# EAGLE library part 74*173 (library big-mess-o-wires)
4-bit D type REGISTER, 3-state

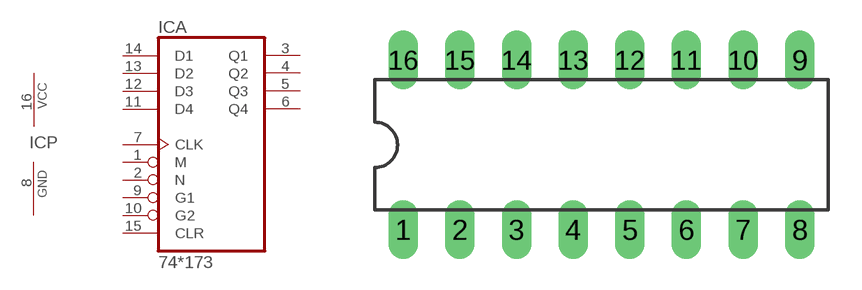
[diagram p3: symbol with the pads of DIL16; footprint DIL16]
Designator prefix IC; gates A=74173 P=PWRN

## 74LS173N  [DIL16]
1  A:M  in
2  A:N  in
3  A:Q1  hiz
4  A:Q2  hiz
5  A:Q3  hiz
6  A:Q4  hiz
7  A:CLK  in
8  P:GND  pwr
9  A:G1  in
10  A:G2  in
11  A:D4  in
12  A:D3  in
13  A:D2  in
14  A:D1  in
15  A:CLR  in
16  P:VCC  pwr

## Footprint DIL16 (pad centres in mm)
Dual In Line Package
drill 0.813 long: 1 -8.89,-3.81; 2 -6.35,-3.81; 3 -3.81,-3.81; 4 -1.27,-3.81; 5 1.27,-3.81; 6 3.81,-3.81; 7 6.35,-3.81; 8 8.89,-3.81; 9 8.89,3.81; 10 6.35,3.81; 11 3.81,3.81; 12 1.27,3.81; 13 -1.27,3.81; 14 -3.81,3.81; 15 -6.35,3.81; 16 -8.89,3.81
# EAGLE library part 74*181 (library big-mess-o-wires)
ARITHMETIC LOGIC UNIT function generator

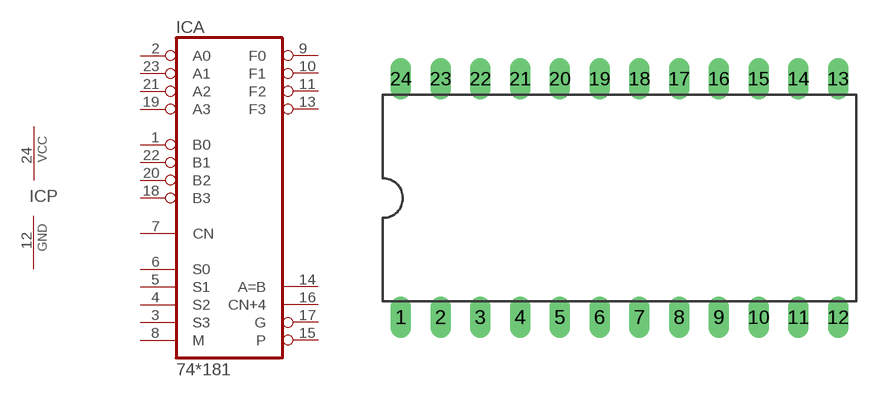
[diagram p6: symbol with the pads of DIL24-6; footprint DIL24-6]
Designator prefix IC; gates A=74181 P=PWRN

## 74LS181N, 74S181N  [DIL24-6]
1  A:B0  in
2  A:A0  in
3  A:S3  in
4  A:S2  in
5  A:S1  in
6  A:S0  in
7  A:CN  in
8  A:M  in
9  A:F0  out
10  A:F1  out
11  A:F2  out
12  P:GND  pwr
13  A:F3  out
14  A:A=B  out
15  A:P  out
16  A:CN+4  out
17  A:G  out
18  A:B3  in
19  A:A3  in
20  A:B2  in
21  A:A2  in
22  A:B1  in
23  A:A1  in
24  P:VCC  pwr

## Footprint DIL24-6 (pad centres in mm)
Dual In Line Package 0.6 inch
drill 0.813 long: 1 -13.97,-7.62; 2 -11.43,-7.62; 3 -8.89,-7.62; 4 -6.35,-7.62; 5 -3.81,-7.62; 6 -1.27,-7.62; 7 1.27,-7.62; 8 3.81,-7.62; 9 6.35,-7.62; 10 8.89,-7.62; 11 11.43,-7.62; 12 13.97,-7.62; 13 13.97,7.62; 14 11.43,7.62; 15 8.89,7.62; 16 6.35,7.62; 17 3.81,7.62; 18 1.27,7.62; 19 -1.27,7.62; 20 -3.81,7.62; 21 -6.35,7.62; 22 -8.89,7.62; 23 -11.43,7.62; 24 -13.97,7.62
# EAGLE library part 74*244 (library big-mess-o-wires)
Octal BUFFER and LINE DRIVER, 3-state

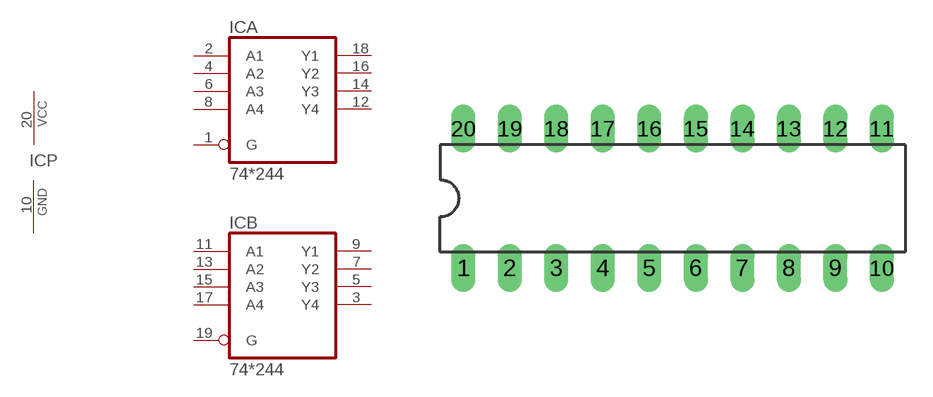
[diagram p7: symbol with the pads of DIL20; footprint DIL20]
Designator prefix IC; gates A=74244 B=74244 P=PWRN

## 74LS244N, 74S244N  [DIL20]
1  A:G  in
2  A:A1  in
3  B:Y4  hiz
4  A:A2  in
5  B:Y3  hiz
6  A:A3  in
7  B:Y2  hiz
8  A:A4  in
9  B:Y1  hiz
10  P:GND  pwr
11  B:A1  in
12  A:Y4  hiz
13  B:A2  in
14  A:Y3  hiz
15  B:A3  in
16  A:Y2  hiz
17  B:A4  in
18  A:Y1  hiz
19  B:G  in
20  P:VCC  pwr

## Footprint DIL20 (pad centres in mm)
Dual In Line Package
drill 0.813 long: 1 -11.43,-3.81; 2 -8.89,-3.81; 3 -6.35,-3.81; 4 -3.81,-3.81; 5 -1.27,-3.81; 6 1.27,-3.81; 7 3.81,-3.81; 8 6.35,-3.81; 9 8.89,-3.81; 10 11.43,-3.81; 11 11.43,3.81; 12 8.89,3.81; 13 6.35,3.81; 14 3.81,3.81; 15 1.27,3.81; 16 -1.27,3.81; 17 -3.81,3.81; 18 -6.35,3.81; 19 -8.89,3.81; 20 -11.43,3.81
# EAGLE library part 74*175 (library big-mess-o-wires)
Qadruple D type FLIP FLOP, clear

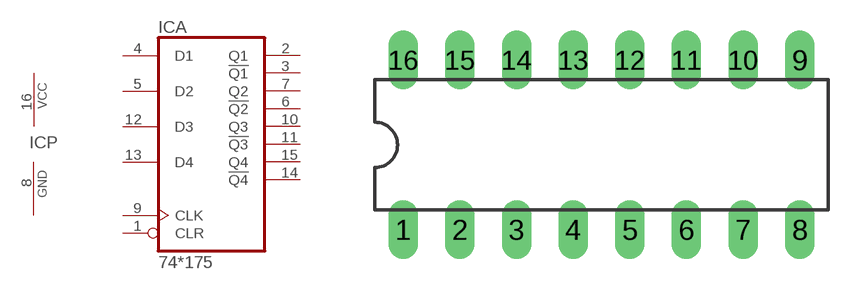
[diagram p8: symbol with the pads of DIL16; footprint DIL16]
Designator prefix IC; gates A=74175 P=PWRN

## 74175N, 74LS175N, 74S175N  [DIL16]
1  A:CLR  in
2  A:Q1  out
3  A:!Q1  out
4  A:D1  in
5  A:D2  in
6  A:!Q2  out
7  A:Q2  out
8  P:GND  pwr
9  A:CLK  in
10  A:Q3  out
11  A:!Q3  out
12  A:D3  in
13  A:D4  in
14  A:!Q4  out
15  A:Q4  out
16  P:VCC  pwr

## Footprint DIL16 (pad centres in mm)
Dual In Line Package
drill 0.813 long: 1 -8.89,-3.81; 2 -6.35,-3.81; 3 -3.81,-3.81; 4 -1.27,-3.81; 5 1.27,-3.81; 6 3.81,-3.81; 7 6.35,-3.81; 8 8.89,-3.81; 9 8.89,3.81; 10 6.35,3.81; 11 3.81,3.81; 12 1.27,3.81; 13 -1.27,3.81; 14 -3.81,3.81; 15 -6.35,3.81; 16 -8.89,3.81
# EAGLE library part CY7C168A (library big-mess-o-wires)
MEMORY

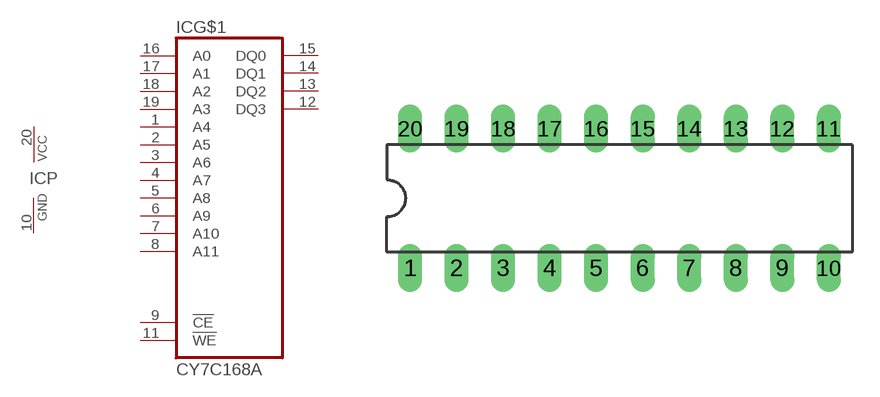
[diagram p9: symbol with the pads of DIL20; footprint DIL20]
Designator prefix IC; gates G$1=CY7C168A P=PWRN-2

## CY7C168A  [DIL20]
1  G$1:A4  in
2  G$1:A5  in
3  G$1:A6  in
4  G$1:A7  in
5  G$1:A8  in
6  G$1:A9  in
7  G$1:A10  in
8  G$1:A11  in
9  G$1:!CE  in
10  P:GND  pwr
11  G$1:!WE  in
12  G$1:DQ3
13  G$1:DQ2
14  G$1:DQ1
15  G$1:DQ0
16  G$1:A0  in
17  G$1:A1  in
18  G$1:A2  in
19  G$1:A3  in
20  P:VCC  pwr

## Footprint DIL20 (pad centres in mm)
Dual In Line Package
drill 0.813 long: 1 -11.43,-3.81; 2 -8.89,-3.81; 3 -6.35,-3.81; 4 -3.81,-3.81; 5 -1.27,-3.81; 6 1.27,-3.81; 7 3.81,-3.81; 8 6.35,-3.81; 9 8.89,-3.81; 10 11.43,-3.81; 11 11.43,3.81; 12 8.89,3.81; 13 6.35,3.81; 14 3.81,3.81; 15 1.27,3.81; 16 -1.27,3.81; 17 -3.81,3.81; 18 -6.35,3.81; 19 -8.89,3.81; 20 -11.43,3.81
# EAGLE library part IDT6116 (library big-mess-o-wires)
MEMORY

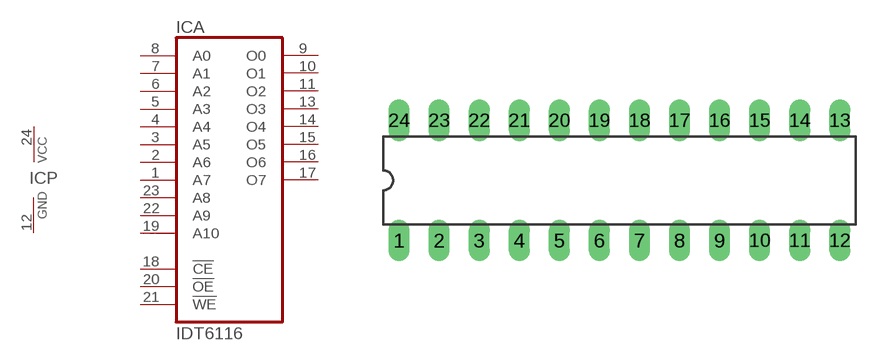
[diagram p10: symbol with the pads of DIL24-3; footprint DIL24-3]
Designator prefix IC; gates A=IDT6116 P=PWRN-1

## IDT6116  [DIL24-3]
1  A:A7  in
2  A:A6  in
3  A:A5  in
4  A:A4  in
5  A:A3  in
6  A:A2  in
7  A:A1  in
8  A:A0  in
9  A:O0  hiz
10  A:O1  hiz
11  A:O2  hiz
12  P:GND  pwr
13  A:O3  hiz
14  A:O4  hiz
15  A:O5  hiz
16  A:O6  hiz
17  A:O7  hiz
18  A:!CE  in
19  A:A10  in
20  A:!OE  in
21  A:!WE  in
22  A:A9  in
23  A:A8  in
24  P:VCC  pwr

## Footprint DIL24-3 (pad centres in mm)
Dual In Line Package 0.3 inch
drill 0.813 long: 1 -13.97,-3.81; 2 -11.43,-3.81; 3 -8.89,-3.81; 4 -6.35,-3.81; 5 -3.81,-3.81; 6 -1.27,-3.81; 7 1.27,-3.81; 8 3.81,-3.81; 9 6.35,-3.81; 10 8.89,-3.81; 11 11.43,-3.81; 12 13.97,-3.81; 13 13.97,3.81; 14 11.43,3.81; 15 8.89,3.81; 16 6.35,3.81; 17 3.81,3.81; 18 1.27,3.81; 19 -1.27,3.81; 20 -3.81,3.81; 21 -6.35,3.81; 22 -8.89,3.81; 23 -11.43,3.81; 24 -13.97,3.81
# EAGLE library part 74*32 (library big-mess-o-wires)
Quad 2-input OR gate

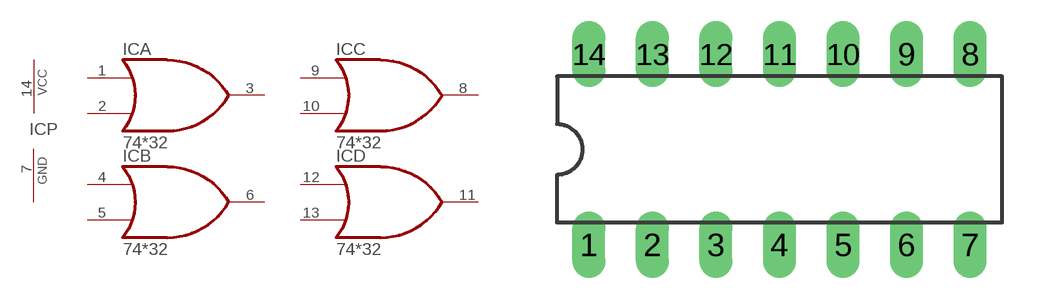
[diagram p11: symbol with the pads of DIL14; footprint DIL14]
Designator prefix IC; gates A=7432 B=7432 C=7432 D=7432 P=PWRN

## 7432N, 74*32N  [DIL14]
1  A:I0  in
2  A:I1  in
3  A:O  out
4  B:I0  in
5  B:I1  in
6  B:O  out
7  P:GND  pwr
8  C:O  out
9  C:I0  in
10  C:I1  in
11  D:O  out
12  D:I0  in
13  D:I1  in
14  P:VCC  pwr

## Footprint DIL14 (pad centres in mm)
Dual In Line Package
drill 0.813 long: 1 -7.62,-3.81; 2 -5.08,-3.81; 3 -2.54,-3.81; 4 0,-3.81; 5 2.54,-3.81; 6 5.08,-3.81; 7 7.62,-3.81; 8 7.62,3.81; 9 5.08,3.81; 10 2.54,3.81; 11 0,3.81; 12 -2.54,3.81; 13 -5.08,3.81; 14 -7.62,3.81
